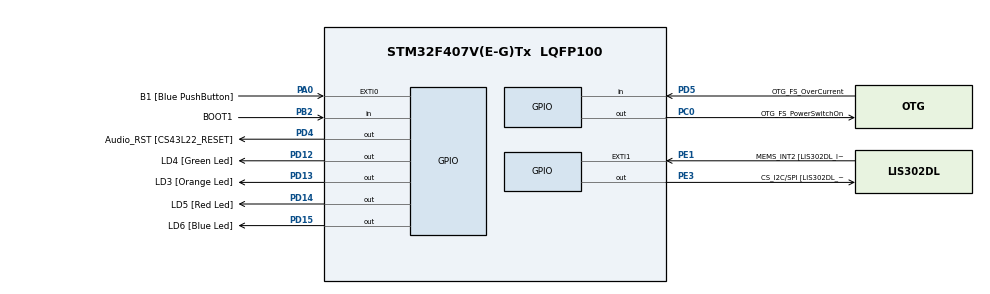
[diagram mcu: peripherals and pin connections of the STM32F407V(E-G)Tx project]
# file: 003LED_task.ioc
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Mcu.Family=STM32F4
Mcu.Name=STM32F407V(E-G)Tx
Mcu.Package=LQFP100
NVIC.PriorityGroup=NVIC_PRIORITYGROUP_4
NVIC.TIM6_DAC_IRQn=true\:0\:0\:false\:false\:true\:false\:true\:true
NVIC.TimeBase=TIM6_DAC_IRQn
NVIC.TimeBaseIP=TIM6
PA0-WKUP.GPIO_Label=B1 [Blue PushButton]
PA0-WKUP.Signal=GPXTI0
PA10.GPIO_Label=OTG_FS_ID
PA10.GPIO_Mode=GPIO_MODE_AF_PP
PA10.GPIO_PuPd=GPIO_NOPULL
PA10.GPIO_Speed=GPIO_SPEED_FREQ_LOW
PA10.Signal=USB_OTG_FS_ID
PA11.GPIO_Label=OTG_FS_DM
PA11.GPIO_Mode=GPIO_MODE_AF_PP
PA11.GPIO_PuPd=GPIO_NOPULL
PA11.GPIO_Speed=GPIO_SPEED_FREQ_LOW
PA11.Signal=USB_OTG_FS_DM
PA12.GPIO_Label=OTG_FS_DP
PA12.GPIO_Mode=GPIO_MODE_AF_PP
PA12.GPIO_PuPd=GPIO_NOPULL
PA12.GPIO_Speed=GPIO_SPEED_FREQ_LOW
PA12.Signal=USB_OTG_FS_DP
PA13.GPIO_Label=SWDIO
PA13.Signal=SYS_JTMS-SWDIO
PA14.GPIO_Label=SWCLK
PA14.Signal=SYS_JTCK-SWCLK
PA4.GPIO_Label=I2S3_WS [CS43L22_LRCK]
PA4.GPIO_Mode=GPIO_MODE_AF_PP
PA4.GPIO_PuPd=GPIO_NOPULL
PA4.GPIO_Speed=GPIO_SPEED_FREQ_LOW
PA4.Signal=I2S3_WS
PA5.GPIO_Label=SPI1_SCK [LIS302DL_SCL/SPC]
PA5.GPIO_Mode=GPIO_MODE_AF_PP
PA5.GPIO_PuPd=GPIO_NOPULL
PA5.GPIO_Speed=GPIO_SPEED_FREQ_LOW
PA5.Signal=SPI1_SCK
PA6.GPIO_Label=SPI1_MISO [LIS302DL_SDO]
PA6.GPIO_Mode=GPIO_MODE_AF_PP
PA6.GPIO_PuPd=GPIO_NOPULL
PA6.GPIO_Speed=GPIO_SPEED_FREQ_LOW
PA6.Signal=SPI1_MISO
PA7.GPIO_Label=SPI1_MOSI [LIS302DL_SDA/SDI/SDO]
PA7.GPIO_Mode=GPIO_MODE_AF_PP
PA7.GPIO_PuPd=GPIO_NOPULL
PA7.GPIO_Speed=GPIO_SPEED_FREQ_LOW
PA7.Signal=SPI1_MOSI
PA9.GPIO_Label=VBUS_FS
PA9.GPIO_Mode=GPIO_MODE_INPUT
PA9.GPIO_PuPd=GPIO_NOPULL
PA9.Signal=USB_OTG_FS_VBUS
PB10.GPIO_Label=CLK_IN [MP45DT02_CLK]
PB10.GPIO_Mode=GPIO_MODE_AF_PP
PB10.GPIO_PuPd=GPIO_NOPULL
PB10.GPIO_Speed=GPIO_SPEED_FREQ_LOW
PB10.Signal=I2S2_CK
PB2.GPIO_Label=BOOT1
PB2.GPIO_Mode=GPIO_MODE_INPUT
PB2.GPIO_PuPd=GPIO_NOPULL
PB2.Signal=GPIO_Input
PB3.GPIO_Label=SWO
PB3.Signal=SYS_JTDO-SWO
PB6.GPIO_Label=Audio_SCL [CS43L22_SCL]
PB6.GPIO_Mode=GPIO_MODE_AF_OD
PB6.GPIO_PuPd=GPIO_NOPULL
PB6.GPIO_Speed=GPIO_SPEED_FREQ_LOW
PB6.Signal=I2C1_SCL
PB9.GPIO_Label=Audio_SDA [CS43L22_SDA]
PB9.GPIO_Mode=GPIO_MODE_AF_OD
PB9.GPIO_PuPd=GPIO_NOPULL
PB9.GPIO_Speed=GPIO_SPEED_FREQ_LOW
PB9.Signal=I2C1_SDA
PC0.GPIO_Label=OTG_FS_PowerSwitchOn
PC0.GPIO_PuPd=GPIO_NOPULL
PC0.GPIO_Speed=GPIO_SPEED_FREQ_LOW
PC0.PinState=GPIO_PIN_SET
PC0.Signal=GPIO_Output
PC10.GPIO_Label=I2S3_SCK [CS43L22_SCLK]
PC10.GPIO_Mode=GPIO_MODE_AF_PP
PC10.GPIO_PuPd=GPIO_NOPULL
PC10.GPIO_Speed=GPIO_SPEED_FREQ_LOW
PC10.Signal=I2S3_CK
PC12.GPIO_Label=I2S3_SD [CS43L22_SDIN]
PC12.GPIO_Mode=GPIO_MODE_AF_PP
PC12.GPIO_PuPd=GPIO_NOPULL
PC12.GPIO_Speed=GPIO_SPEED_FREQ_LOW
PC12.Signal=I2S3_SD
PC14-OSC32_IN.GPIO_Label=PC14-OSC32_IN
PC14-OSC32_IN.Signal=RCC_OSC32_IN
PC15-OSC32_OUT.GPIO_Label=PC15-OSC32_OUT
PC15-OSC32_OUT.Signal=RCC_OSC32_OUT
PC3.GPIO_Label=PDM_OUT [MP45DT02_DOUT]
PC3.GPIO_Mode=GPIO_MODE_AF_PP
PC3.GPIO_PuPd=GPIO_NOPULL
PC3.GPIO_Speed=GPIO_SPEED_FREQ_LOW
PC3.Signal=I2S2_SD
PC7.GPIO_Label=I2S3_MCK [CS43L22_MCLK]
PC7.GPIO_Mode=GPIO_MODE_AF_PP
PC7.GPIO_PuPd=GPIO_NOPULL
PC7.GPIO_Speed=GPIO_SPEED_FREQ_LOW
PC7.Signal=I2S3_MCK
PD12.GPIO_Label=LD4 [Green Led]
PD12.GPIO_PuPd=GPIO_NOPULL
PD12.GPIO_Speed=GPIO_SPEED_FREQ_LOW
PD12.Signal=GPIO_Output
PD13.GPIO_Label=LD3 [Orange Led]
PD13.GPIO_PuPd=GPIO_NOPULL
PD13.GPIO_Speed=GPIO_SPEED_FREQ_LOW
PD13.Signal=GPIO_Output
PD14.GPIO_Label=LD5 [Red Led]
PD14.GPIO_PuPd=GPIO_NOPULL
PD14.GPIO_Speed=GPIO_SPEED_FREQ_LOW
PD14.Signal=GPIO_Output
PD15.GPIO_Label=LD6 [Blue Led]
PD15.GPIO_PuPd=GPIO_NOPULL
PD15.GPIO_Speed=GPIO_SPEED_FREQ_LOW
PD15.Signal=GPIO_Output
PD4.GPIO_Label=Audio_RST [CS43L22_RESET]
PD4.GPIO_PuPd=GPIO_NOPULL
PD4.GPIO_Speed=GPIO_SPEED_FREQ_LOW
PD4.Signal=GPIO_Output
PD5.GPIO_Label=OTG_FS_OverCurrent
PD5.GPIO_Mode=GPIO_MODE_INPUT
PD5.GPIO_PuPd=GPIO_NOPULL
PD5.Signal=GPIO_Input
PE1.GPIO_Label=MEMS_INT2 [LIS302DL_INT2]
PE1.GPIO_ModeDefaultEXTI=GPIO_MODE_EVT_RISING
PE1.GPIO_PuPd=GPIO_NOPULL
PE1.Signal=GPXTI1
PE3.GPIO_Label=CS_I2C/SPI [LIS302DL_CS_I2C/SPI]
PE3.GPIO_PuPd=GPIO_NOPULL
PE3.GPIO_Speed=GPIO_SPEED_FREQ_LOW
PE3.Signal=GPIO_Output
PH0-OSC_IN.GPIO_Label=PH0-OSC_IN
PH0-OSC_IN.Signal=RCC_OSC_IN
PH1-OSC_OUT.GPIO_Label=PH1-OSC_OUT
PH1-OSC_OUT.Signal=RCC_OSC_OUT
ProjectManager.HeapSize=0x200
ProjectManager.StackSize=0x400
ProjectManager.TargetToolchain=STM32CubeIDE
RCC.48MHZClocksFreq_Value=48000000
RCC.AHBFreq_Value=168000000
RCC.APB1CLKDivider=RCC_HCLK_DIV4
RCC.APB1Freq_Value=42000000
RCC.APB1TimFreq_Value=84000000
RCC.APB2CLKDivider=RCC_HCLK_DIV2
RCC.APB2Freq_Value=84000000
RCC.APB2TimFreq_Value=168000000
RCC.CortexFreq_Value=168000000
RCC.HCLKFreq_Value=168000000
RCC.HSE_VALUE=8000000
RCC.HSI_VALUE=16000000
RCC.LSE_VALUE=32768
RCC.PLLM=8
RCC.PLLN=168
RCC.PLLQ=7
RCC.SYSCLKFreq_VALUE=168000000
RCC.SYSCLKSource=RCC_SYSCLKSOURCE_PLLCLK
RCC.VCOOutputFreq_Value=336000000
VP_SYS_VS_tim6.Mode=TIM6
board=STM32F407G-DISC1

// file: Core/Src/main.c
/* USER CODE BEGIN Header */
/**
  ******************************************************************************
  * @file           : main.c
  * @brief          : Main program body
  ******************************************************************************
  * @attention
  *
  * <h2><center>&copy; Copyright (c) 2021 STMicroelectronics.
  * All rights reserved.</center></h2>
  *
  * This software component is licensed by ST under BSD 3-Clause license,
  * the "License"; You may not use this file except in compliance with the
  * License. You may obtain a copy of the License at:
  *                        opensource.org/licenses/BSD-3-Clause
  *
  ******************************************************************************
  */
/* USER CODE END Header */
#include "main.h"

/* USER CODE BEGIN Includes */

#include "FreeRTOS.h"
#include "task.h"
#include<stdio.h>

/* USER CODE END Includes */

/* USER CODE BEGIN PV */

#define DWT_CTRL    (*(volatile uint32_t*)0xE0001000)

/* USER CODE END PV */

void SystemClock_Config(void);
static void MX_GPIO_Init(void);
/* USER CODE BEGIN PFP */

static void led_green_handler(void* parameters);
static void led_orange_handler(void* parameters);
static void led_red_handler(void* parameters);

//extern void SEGGER_UART_init(uint32_t);

/* USER CODE END PFP */

int main(void)
{

  /* USER CODE BEGIN 1 */
	TaskHandle_t task1_handle;
	TaskHandle_t task2_handle;
	TaskHandle_t task3_handle;
	BaseType_t status;

  /* USER CODE END 1 */

  /* MCU Configuration--------------------------------------------------------*/

  /* Reset of all peripherals, Initializes the Flash interface and the Systick. */
  HAL_Init();

  /* Configure the system clock */
  SystemClock_Config();

  /* Initialize all configured peripherals */
  MX_GPIO_Init();
  /* USER CODE BEGIN 2 */

  //SEGGER_UART_init(500000);

  //CYCLCNT enable
  // Enable DWT and ITM
  DWT_CTRL |= (1 << 0);

  SEGGER_SYSVIEW_Conf();
  SEGGER_SYSVIEW_Start();

  status = xTaskCreate(led_green_handler, "LED_green_task", 200, NULL, 2, &task1_handle);

  configASSERT(status == pdPASS);

  status = xTaskCreate(led_red_handler, "LED_red_task", 200,NULL, 2, &task2_handle);

  configASSERT(status == pdPASS);

  status = xTaskCreate(led_orange_handler, "LED_orange_task", 200, NULL, 2, &task3_handle);

  configASSERT(status == pdPASS);

  //start the freeRTOS scheduler
  vTaskStartScheduler();

  /* USER CODE END 2 */

  /* Infinite loop */
  while (1)
  {

  }
}

void SystemClock_Config(void)
{
  RCC_OscInitTypeDef RCC_OscInitStruct = {0};
  RCC_ClkInitTypeDef RCC_ClkInitStruct = {0};

  /** Configure the main internal regulator output voltage
  */
  __HAL_RCC_PWR_CLK_ENABLE();
  __HAL_PWR_VOLTAGESCALING_CONFIG(PWR_REGULATOR_VOLTAGE_SCALE1);

  /** Initializes the RCC Oscillators according to the specified parameters
  * in the RCC_OscInitTypeDef structure.
  */
  RCC_OscInitStruct.OscillatorType = RCC_OSCILLATORTYPE_HSI;
  RCC_OscInitStruct.HSIState = RCC_HSI_ON;
  RCC_OscInitStruct.HSICalibrationValue = RCC_HSICALIBRATION_DEFAULT;
  RCC_OscInitStruct.PLL.PLLState = RCC_PLL_ON;
  RCC_OscInitStruct.PLL.PLLSource = RCC_PLLSOURCE_HSI;
  RCC_OscInitStruct.PLL.PLLM = 8;
  RCC_OscInitStruct.PLL.PLLN = 50;
  RCC_OscInitStruct.PLL.PLLP = RCC_PLLP_DIV4;
  RCC_OscInitStruct.PLL.PLLQ = 7;
  if (HAL_RCC_OscConfig(&RCC_OscInitStruct) != HAL_OK)
  {
    Error_Handler();
  }

  /** Initializes the CPU, AHB and APB buses clocks
  */
  RCC_ClkInitStruct.ClockType = RCC_CLOCKTYPE_HCLK|RCC_CLOCKTYPE_SYSCLK
                              |RCC_CLOCKTYPE_PCLK1|RCC_CLOCKTYPE_PCLK2;
  RCC_ClkInitStruct.SYSCLKSource = RCC_SYSCLKSOURCE_PLLCLK;
  RCC_ClkInitStruct.AHBCLKDivider = RCC_SYSCLK_DIV1;
  RCC_ClkInitStruct.APB1CLKDivider = RCC_HCLK_DIV4;
  RCC_ClkInitStruct.APB2CLKDivider = RCC_HCLK_DIV2;

  if (HAL_RCC_ClockConfig(&RCC_ClkInitStruct, FLASH_LATENCY_0) != HAL_OK)
  {
    Error_Handler();
  }
}

static void MX_GPIO_Init(void)
{
  GPIO_InitTypeDef GPIO_InitStruct = {0};

  /* GPIO Ports Clock Enable */
  __HAL_RCC_GPIOE_CLK_ENABLE();
  __HAL_RCC_GPIOC_CLK_ENABLE();
  __HAL_RCC_GPIOH_CLK_ENABLE();
  __HAL_RCC_GPIOA_CLK_ENABLE();
  __HAL_RCC_GPIOB_CLK_ENABLE();
  __HAL_RCC_GPIOD_CLK_ENABLE();

  /*Configure GPIO pin Output Level */
  HAL_GPIO_WritePin(CS_I2C_SPI_GPIO_Port, CS_I2C_SPI_Pin, GPIO_PIN_RESET);

  /*Configure GPIO pin Output Level */
  HAL_GPIO_WritePin(OTG_FS_PowerSwitchOn_GPIO_Port, OTG_FS_PowerSwitchOn_Pin, GPIO_PIN_SET);

  /*Configure GPIO pin Output Level */
  HAL_GPIO_WritePin(GPIOD, LD4_Pin|LD3_Pin|LD5_Pin|LD6_Pin
                          |Audio_RST_Pin, GPIO_PIN_RESET);

  /*Configure GPIO pin : CS_I2C_SPI_Pin */
  GPIO_InitStruct.Pin = CS_I2C_SPI_Pin;
  GPIO_InitStruct.Mode = GPIO_MODE_OUTPUT_PP;
  GPIO_InitStruct.Pull = GPIO_NOPULL;
  GPIO_InitStruct.Speed = GPIO_SPEED_FREQ_LOW;
  HAL_GPIO_Init(CS_I2C_SPI_GPIO_Port, &GPIO_InitStruct);

  /*Configure GPIO pin : OTG_FS_PowerSwitchOn_Pin */
  GPIO_InitStruct.Pin = OTG_FS_PowerSwitchOn_Pin;
  GPIO_InitStruct.Mode = GPIO_MODE_OUTPUT_PP;
  GPIO_InitStruct.Pull = GPIO_NOPULL;
  GPIO_InitStruct.Speed = GPIO_SPEED_FREQ_LOW;
  HAL_GPIO_Init(OTG_FS_PowerSwitchOn_GPIO_Port, &GPIO_InitStruct);

  /*Configure GPIO pin : PDM_OUT_Pin */
  GPIO_InitStruct.Pin = PDM_OUT_Pin;
  GPIO_InitStruct.Mode = GPIO_MODE_AF_PP;
  GPIO_InitStruct.Pull = GPIO_NOPULL;
  GPIO_InitStruct.Speed = GPIO_SPEED_FREQ_LOW;
  GPIO_InitStruct.Alternate = GPIO_AF5_SPI2;
  HAL_GPIO_Init(PDM_OUT_GPIO_Port, &GPIO_InitStruct);

  /*Configure GPIO pin : B1_Pin */
  GPIO_InitStruct.Pin = B1_Pin;
  GPIO_InitStruct.Mode = GPIO_MODE_IT_RISING;
  GPIO_InitStruct.Pull = GPIO_NOPULL;
  HAL_GPIO_Init(B1_GPIO_Port, &GPIO_InitStruct);

  /*Configure GPIO pin : I2S3_WS_Pin */
  GPIO_InitStruct.Pin = I2S3_WS_Pin;
  GPIO_InitStruct.Mode = GPIO_MODE_AF_PP;
  GPIO_InitStruct.Pull = GPIO_NOPULL;
  GPIO_InitStruct.Speed = GPIO_SPEED_FREQ_LOW;
  GPIO_InitStruct.Alternate = GPIO_AF6_SPI3;
  HAL_GPIO_Init(I2S3_WS_GPIO_Port, &GPIO_InitStruct);

  /*Configure GPIO pins : SPI1_SCK_Pin SPI1_MISO_Pin SPI1_MOSI_Pin */
  GPIO_InitStruct.Pin = SPI1_SCK_Pin|SPI1_MISO_Pin|SPI1_MOSI_Pin;
  GPIO_InitStruct.Mode = GPIO_MODE_AF_PP;
  GPIO_InitStruct.Pull = GPIO_NOPULL;
  GPIO_InitStruct.Speed = GPIO_SPEED_FREQ_LOW;
  GPIO_InitStruct.Alternate = GPIO_AF5_SPI1;
  HAL_GPIO_Init(GPIOA, &GPIO_InitStruct);

  /*Configure GPIO pin : BOOT1_Pin */
  GPIO_InitStruct.Pin = BOOT1_Pin;
  GPIO_InitStruct.Mode = GPIO_MODE_INPUT;
  GPIO_InitStruct.Pull = GPIO_NOPULL;
  HAL_GPIO_Init(BOOT1_GPIO_Port, &GPIO_InitStruct);

  /*Configure GPIO pin : CLK_IN_Pin */
  GPIO_InitStruct.Pin = CLK_IN_Pin;
  GPIO_InitStruct.Mode = GPIO_MODE_AF_PP;
  GPIO_InitStruct.Pull = GPIO_NOPULL;
  GPIO_InitStruct.Speed = GPIO_SPEED_FREQ_LOW;
  GPIO_InitStruct.Alternate = GPIO_AF5_SPI2;
  HAL_GPIO_Init(CLK_IN_GPIO_Port, &GPIO_InitStruct);

  /*Configure GPIO pins : LD4_Pin LD3_Pin LD5_Pin LD6_Pin
                           Audio_RST_Pin */
  GPIO_InitStruct.Pin = LD4_Pin|LD3_Pin|LD5_Pin|LD6_Pin
                          |Audio_RST_Pin;
  GPIO_InitStruct.Mode = GPIO_MODE_OUTPUT_PP;
  GPIO_InitStruct.Pull = GPIO_NOPULL;
  GPIO_InitStruct.Speed = GPIO_SPEED_FREQ_LOW;
  HAL_GPIO_Init(GPIOD, &GPIO_InitStruct);

  /*Configure GPIO pins : I2S3_MCK_Pin I2S3_SCK_Pin I2S3_SD_Pin */
  GPIO_InitStruct.Pin = I2S3_MCK_Pin|I2S3_SCK_Pin|I2S3_SD_Pin;
  GPIO_InitStruct.Mode = GPIO_MODE_AF_PP;
  GPIO_InitStruct.Pull = GPIO_NOPULL;
  GPIO_InitStruct.Speed = GPIO_SPEED_FREQ_LOW;
  GPIO_InitStruct.Alternate = GPIO_AF6_SPI3;
  HAL_GPIO_Init(GPIOC, &GPIO_InitStruct);

  /*Configure GPIO pin : VBUS_FS_Pin */
  GPIO_InitStruct.Pin = VBUS_FS_Pin;
  GPIO_InitStruct.Mode = GPIO_MODE_INPUT;
  GPIO_InitStruct.Pull = GPIO_NOPULL;
  HAL_GPIO_Init(VBUS_FS_GPIO_Port, &GPIO_InitStruct);

  /*Configure GPIO pins : OTG_FS_ID_Pin OTG_FS_DM_Pin OTG_FS_DP_Pin */
  GPIO_InitStruct.Pin = OTG_FS_ID_Pin|OTG_FS_DM_Pin|OTG_FS_DP_Pin;
  GPIO_InitStruct.Mode = GPIO_MODE_AF_PP;
  GPIO_InitStruct.Pull = GPIO_NOPULL;
  GPIO_InitStruct.Speed = GPIO_SPEED_FREQ_LOW;
  GPIO_InitStruct.Alternate = GPIO_AF10_OTG_FS;
  HAL_GPIO_Init(GPIOA, &GPIO_InitStruct);

  /*Configure GPIO pin : OTG_FS_OverCurrent_Pin */
  GPIO_InitStruct.Pin = OTG_FS_OverCurrent_Pin;
  GPIO_InitStruct.Mode = GPIO_MODE_INPUT;
  GPIO_InitStruct.Pull = GPIO_NOPULL;
  HAL_GPIO_Init(OTG_FS_OverCurrent_GPIO_Port, &GPIO_InitStruct);

  /*Configure GPIO pins : Audio_SCL_Pin Audio_SDA_Pin */
  GPIO_InitStruct.Pin = Audio_SCL_Pin|Audio_SDA_Pin;
  GPIO_InitStruct.Mode = GPIO_MODE_AF_OD;
  GPIO_InitStruct.Pull = GPIO_NOPULL;
  GPIO_InitStruct.Speed = GPIO_SPEED_FREQ_LOW;
  GPIO_InitStruct.Alternate = GPIO_AF4_I2C1;
  HAL_GPIO_Init(GPIOB, &GPIO_InitStruct);

  /*Configure GPIO pin : MEMS_INT2_Pin */
  GPIO_InitStruct.Pin = MEMS_INT2_Pin;
  GPIO_InitStruct.Mode = GPIO_MODE_EVT_RISING;
  GPIO_InitStruct.Pull = GPIO_NOPULL;
  HAL_GPIO_Init(MEMS_INT2_GPIO_Port, &GPIO_InitStruct);

}

/* USER CODE BEGIN 4 */

static void led_green_handler(void* parameters)
{

	while(1)
	{
		SEGGER_SYSVIEW_PrintfTarget("Toggling green LED");
		HAL_GPIO_TogglePin(GPIOD, LED_GREEN_PIN);
		vTaskDelay(pdMS_TO_TICKS(1000));
	}

}

static void led_orange_handler(void* parameters)
{
	while(1)
	{
		SEGGER_SYSVIEW_PrintfTarget("Toggling orange LED");
		HAL_GPIO_TogglePin(GPIOD, LED_ORANGE_PIN);
		vTaskDelay(pdMS_TO_TICKS(800));
	}

}

static void led_red_handler(void* parameters)
{
	while(1)
	{
		SEGGER_SYSVIEW_PrintfTarget("Toggling red LED");
		HAL_GPIO_TogglePin(GPIOD, LED_RED_PIN);
		vTaskDelay(pdMS_TO_TICKS(400));
	}

}

/* USER CODE END 4 */

void HAL_TIM_PeriodElapsedCallback(TIM_HandleTypeDef *htim)
{
  if (htim->Instance == TIM6)
  {
    HAL_IncTick();
  }
}

void Error_Handler(void)
{
}
